VERSION 5.7 ;
BUSBITCHARS "[]" ;
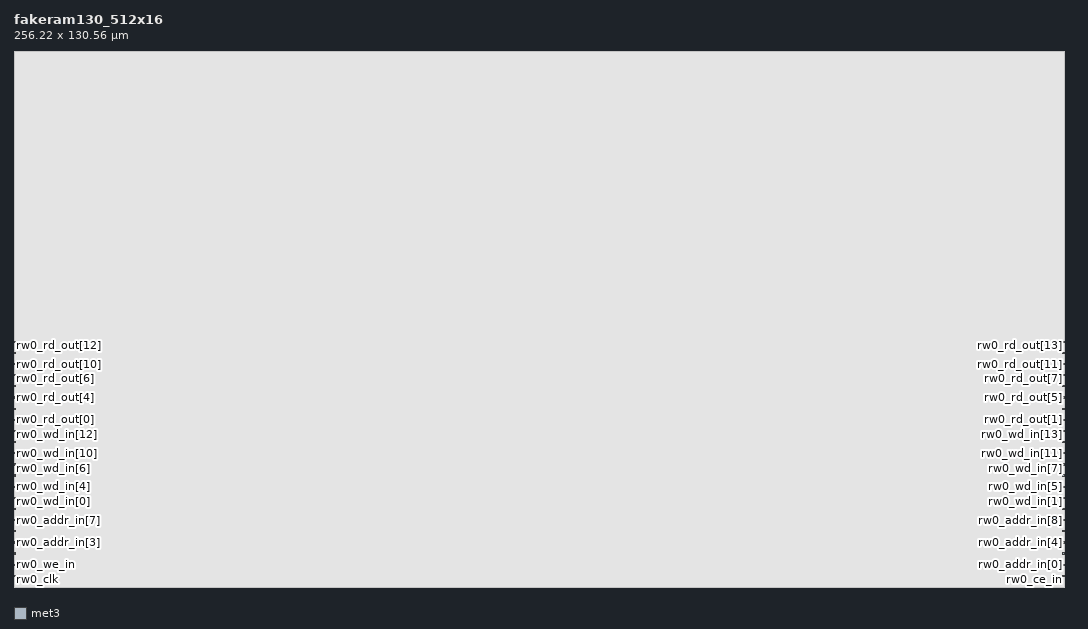
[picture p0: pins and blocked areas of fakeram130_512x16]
MACRO fakeram130_512x16
  FOREIGN fakeram130_512x16 0 0 ;
  SYMMETRY X Y R90 ;
  SIZE 256.220 BY 130.560 ;
  CLASS BLOCK ;
  PIN rw0_clk
    DIRECTION INPUT ;
    USE SIGNAL ;
    SHAPE ABUTMENT ;
    PORT
      LAYER met3 ;
      RECT 0.000 2.570 0.300 2.870 ;
    END
  END rw0_clk
  PIN rw0_ce_in
    DIRECTION INPUT ;
    USE SIGNAL ;
    SHAPE ABUTMENT ;
    PORT
      LAYER met3 ;
      RECT 255.920 2.570 256.220 2.870 ;
    END
  END rw0_ce_in
  PIN rw0_we_in
    DIRECTION INPUT ;
    USE SIGNAL ;
    SHAPE ABUTMENT ;
    PORT
      LAYER met3 ;
      RECT 0.000 5.290 0.300 5.590 ;
    END
  END rw0_we_in
  PIN rw0_addr_in[0]
    DIRECTION INPUT ;
    USE SIGNAL ;
    SHAPE ABUTMENT ;
    PORT
      LAYER met3 ;
      RECT 255.920 5.290 256.220 5.590 ;
    END
  END rw0_addr_in[0]
  PIN rw0_addr_in[1]
    DIRECTION INPUT ;
    USE SIGNAL ;
    SHAPE ABUTMENT ;
    PORT
      LAYER met3 ;
      RECT 0.000 8.010 0.300 8.310 ;
    END
  END rw0_addr_in[1]
  PIN rw0_addr_in[2]
    DIRECTION INPUT ;
    USE SIGNAL ;
    SHAPE ABUTMENT ;
    PORT
      LAYER met3 ;
      RECT 255.920 8.010 256.220 8.310 ;
    END
  END rw0_addr_in[2]
  PIN rw0_addr_in[3]
    DIRECTION INPUT ;
    USE SIGNAL ;
    SHAPE ABUTMENT ;
    PORT
      LAYER met3 ;
      RECT 0.000 10.730 0.300 11.030 ;
    END
  END rw0_addr_in[3]
  PIN rw0_addr_in[4]
    DIRECTION INPUT ;
    USE SIGNAL ;
    SHAPE ABUTMENT ;
    PORT
      LAYER met3 ;
      RECT 255.920 10.730 256.220 11.030 ;
    END
  END rw0_addr_in[4]
  PIN rw0_addr_in[5]
    DIRECTION INPUT ;
    USE SIGNAL ;
    SHAPE ABUTMENT ;
    PORT
      LAYER met3 ;
      RECT 0.000 13.450 0.300 13.750 ;
    END
  END rw0_addr_in[5]
  PIN rw0_addr_in[6]
    DIRECTION INPUT ;
    USE SIGNAL ;
    SHAPE ABUTMENT ;
    PORT
      LAYER met3 ;
      RECT 255.920 13.450 256.220 13.750 ;
    END
  END rw0_addr_in[6]
  PIN rw0_addr_in[7]
    DIRECTION INPUT ;
    USE SIGNAL ;
    SHAPE ABUTMENT ;
    PORT
      LAYER met3 ;
      RECT 0.000 16.170 0.300 16.470 ;
    END
  END rw0_addr_in[7]
  PIN rw0_addr_in[8]
    DIRECTION INPUT ;
    USE SIGNAL ;
    SHAPE ABUTMENT ;
    PORT
      LAYER met3 ;
      RECT 255.920 16.170 256.220 16.470 ;
    END
  END rw0_addr_in[8]
  PIN rw0_wd_in[0]
    DIRECTION INPUT ;
    USE SIGNAL ;
    SHAPE ABUTMENT ;
    PORT
      LAYER met3 ;
      RECT 0.000 18.890 0.300 19.190 ;
    END
  END rw0_wd_in[0]
  PIN rw0_wd_in[1]
    DIRECTION INPUT ;
    USE SIGNAL ;
    SHAPE ABUTMENT ;
    PORT
      LAYER met3 ;
      RECT 255.920 18.890 256.220 19.190 ;
    END
  END rw0_wd_in[1]
  PIN rw0_wd_in[2]
    DIRECTION INPUT ;
    USE SIGNAL ;
    SHAPE ABUTMENT ;
    PORT
      LAYER met3 ;
      RECT 0.000 21.610 0.300 21.910 ;
    END
  END rw0_wd_in[2]
  PIN rw0_wd_in[3]
    DIRECTION INPUT ;
    USE SIGNAL ;
    SHAPE ABUTMENT ;
    PORT
      LAYER met3 ;
      RECT 255.920 21.610 256.220 21.910 ;
    END
  END rw0_wd_in[3]
  PIN rw0_wd_in[4]
    DIRECTION INPUT ;
    USE SIGNAL ;
    SHAPE ABUTMENT ;
    PORT
      LAYER met3 ;
      RECT 0.000 24.330 0.300 24.630 ;
    END
  END rw0_wd_in[4]
  PIN rw0_wd_in[5]
    DIRECTION INPUT ;
    USE SIGNAL ;
    SHAPE ABUTMENT ;
    PORT
      LAYER met3 ;
      RECT 255.920 24.330 256.220 24.630 ;
    END
  END rw0_wd_in[5]
  PIN rw0_wd_in[6]
    DIRECTION INPUT ;
    USE SIGNAL ;
    SHAPE ABUTMENT ;
    PORT
      LAYER met3 ;
      RECT 0.000 27.050 0.300 27.350 ;
    END
  END rw0_wd_in[6]
  PIN rw0_wd_in[7]
    DIRECTION INPUT ;
    USE SIGNAL ;
    SHAPE ABUTMENT ;
    PORT
      LAYER met3 ;
      RECT 255.920 27.050 256.220 27.350 ;
    END
  END rw0_wd_in[7]
  PIN rw0_wd_in[8]
    DIRECTION INPUT ;
    USE SIGNAL ;
    SHAPE ABUTMENT ;
    PORT
      LAYER met3 ;
      RECT 0.000 29.770 0.300 30.070 ;
    END
  END rw0_wd_in[8]
  PIN rw0_wd_in[9]
    DIRECTION INPUT ;
    USE SIGNAL ;
    SHAPE ABUTMENT ;
    PORT
      LAYER met3 ;
      RECT 255.920 29.770 256.220 30.070 ;
    END
  END rw0_wd_in[9]
  PIN rw0_wd_in[10]
    DIRECTION INPUT ;
    USE SIGNAL ;
    SHAPE ABUTMENT ;
    PORT
      LAYER met3 ;
      RECT 0.000 32.490 0.300 32.790 ;
    END
  END rw0_wd_in[10]
  PIN rw0_wd_in[11]
    DIRECTION INPUT ;
    USE SIGNAL ;
    SHAPE ABUTMENT ;
    PORT
      LAYER met3 ;
      RECT 255.920 32.490 256.220 32.790 ;
    END
  END rw0_wd_in[11]
  PIN rw0_wd_in[12]
    DIRECTION INPUT ;
    USE SIGNAL ;
    SHAPE ABUTMENT ;
    PORT
      LAYER met3 ;
      RECT 0.000 35.210 0.300 35.510 ;
    END
  END rw0_wd_in[12]
  PIN rw0_wd_in[13]
    DIRECTION INPUT ;
    USE SIGNAL ;
    SHAPE ABUTMENT ;
    PORT
      LAYER met3 ;
      RECT 255.920 35.210 256.220 35.510 ;
    END
  END rw0_wd_in[13]
  PIN rw0_wd_in[14]
    DIRECTION INPUT ;
    USE SIGNAL ;
    SHAPE ABUTMENT ;
    PORT
      LAYER met3 ;
      RECT 0.000 37.930 0.300 38.230 ;
    END
  END rw0_wd_in[14]
  PIN rw0_wd_in[15]
    DIRECTION INPUT ;
    USE SIGNAL ;
    SHAPE ABUTMENT ;
    PORT
      LAYER met3 ;
      RECT 255.920 37.930 256.220 38.230 ;
    END
  END rw0_wd_in[15]
  PIN rw0_rd_out[0]
    DIRECTION OUTPUT ;
    USE SIGNAL ;
    SHAPE ABUTMENT ;
    PORT
      LAYER met3 ;
      RECT 0.000 40.650 0.300 40.950 ;
    END
  END rw0_rd_out[0]
  PIN rw0_rd_out[1]
    DIRECTION OUTPUT ;
    USE SIGNAL ;
    SHAPE ABUTMENT ;
    PORT
      LAYER met3 ;
      RECT 255.920 40.650 256.220 40.950 ;
    END
  END rw0_rd_out[1]
  PIN rw0_rd_out[2]
    DIRECTION OUTPUT ;
    USE SIGNAL ;
    SHAPE ABUTMENT ;
    PORT
      LAYER met3 ;
      RECT 0.000 43.370 0.300 43.670 ;
    END
  END rw0_rd_out[2]
  PIN rw0_rd_out[3]
    DIRECTION OUTPUT ;
    USE SIGNAL ;
    SHAPE ABUTMENT ;
    PORT
      LAYER met3 ;
      RECT 255.920 43.370 256.220 43.670 ;
    END
  END rw0_rd_out[3]
  PIN rw0_rd_out[4]
    DIRECTION OUTPUT ;
    USE SIGNAL ;
    SHAPE ABUTMENT ;
    PORT
      LAYER met3 ;
      RECT 0.000 46.090 0.300 46.390 ;
    END
  END rw0_rd_out[4]
  PIN rw0_rd_out[5]
    DIRECTION OUTPUT ;
    USE SIGNAL ;
    SHAPE ABUTMENT ;
    PORT
      LAYER met3 ;
      RECT 255.920 46.090 256.220 46.390 ;
    END
  END rw0_rd_out[5]
  PIN rw0_rd_out[6]
    DIRECTION OUTPUT ;
    USE SIGNAL ;
    SHAPE ABUTMENT ;
    PORT
      LAYER met3 ;
      RECT 0.000 48.810 0.300 49.110 ;
    END
  END rw0_rd_out[6]
  PIN rw0_rd_out[7]
    DIRECTION OUTPUT ;
    USE SIGNAL ;
    SHAPE ABUTMENT ;
    PORT
      LAYER met3 ;
      RECT 255.920 48.810 256.220 49.110 ;
    END
  END rw0_rd_out[7]
  PIN rw0_rd_out[8]
    DIRECTION OUTPUT ;
    USE SIGNAL ;
    SHAPE ABUTMENT ;
    PORT
      LAYER met3 ;
      RECT 0.000 51.530 0.300 51.830 ;
    END
  END rw0_rd_out[8]
  PIN rw0_rd_out[9]
    DIRECTION OUTPUT ;
    USE SIGNAL ;
    SHAPE ABUTMENT ;
    PORT
      LAYER met3 ;
      RECT 255.920 51.530 256.220 51.830 ;
    END
  END rw0_rd_out[9]
  PIN rw0_rd_out[10]
    DIRECTION OUTPUT ;
    USE SIGNAL ;
    SHAPE ABUTMENT ;
    PORT
      LAYER met3 ;
      RECT 0.000 54.250 0.300 54.550 ;
    END
  END rw0_rd_out[10]
  PIN rw0_rd_out[11]
    DIRECTION OUTPUT ;
    USE SIGNAL ;
    SHAPE ABUTMENT ;
    PORT
      LAYER met3 ;
      RECT 255.920 54.250 256.220 54.550 ;
    END
  END rw0_rd_out[11]
  PIN rw0_rd_out[12]
    DIRECTION OUTPUT ;
    USE SIGNAL ;
    SHAPE ABUTMENT ;
    PORT
      LAYER met3 ;
      RECT 0.000 56.970 0.300 57.270 ;
    END
  END rw0_rd_out[12]
  PIN rw0_rd_out[13]
    DIRECTION OUTPUT ;
    USE SIGNAL ;
    SHAPE ABUTMENT ;
    PORT
      LAYER met3 ;
      RECT 255.920 56.970 256.220 57.270 ;
    END
  END rw0_rd_out[13]
  PIN rw0_rd_out[14]
    DIRECTION OUTPUT ;
    USE SIGNAL ;
    SHAPE ABUTMENT ;
    PORT
      LAYER met3 ;
      RECT 0.000 59.690 0.300 59.990 ;
    END
  END rw0_rd_out[14]
  PIN rw0_rd_out[15]
    DIRECTION OUTPUT ;
    USE SIGNAL ;
    SHAPE ABUTMENT ;
    PORT
      LAYER met3 ;
      RECT 255.920 59.690 256.220 59.990 ;
    END
  END rw0_rd_out[15]
  OBS
    LAYER li1 ;
      RECT 0.000 0.000 256.220 130.560 ;
    LAYER met1 ;
      RECT 0.000 0.000 256.220 130.560 ;
    LAYER met2 ;
      RECT 0.000 0.000 256.220 130.560 ;
    LAYER met3 ;
      RECT 0.000 0.000 256.220 130.560 ;
    LAYER met4 ;
      RECT 0.000 0.000 256.220 130.560 ;
  END
END fakeram130_512x16
END LIBRARY
